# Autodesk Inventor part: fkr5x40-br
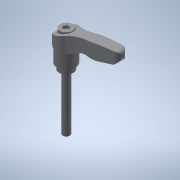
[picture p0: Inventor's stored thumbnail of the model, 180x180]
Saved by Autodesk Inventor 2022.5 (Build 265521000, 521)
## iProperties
Created: 2016-12
Part Number: fkr5x40-br
Material: 一般
Document SubType Name: Modeling
Designer: imaocorp
Density: 1 g/cm^3
Appearance: 既定
Author: imaocorp
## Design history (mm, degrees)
node "fkr5x40-br.x_t1"
node "K1000_105040_012"
node "Base1"
